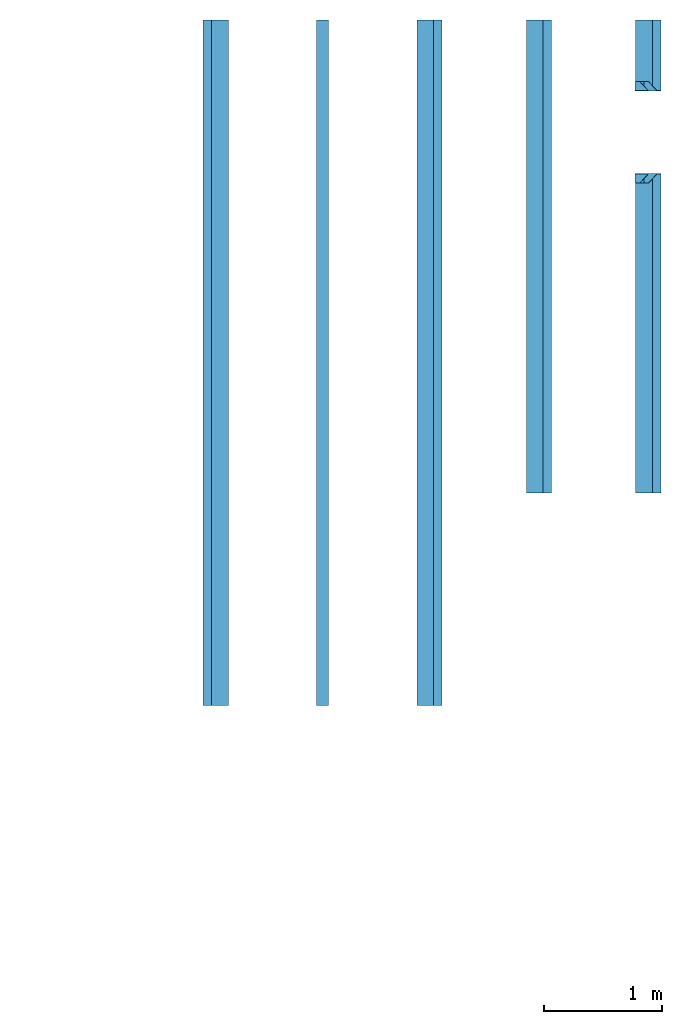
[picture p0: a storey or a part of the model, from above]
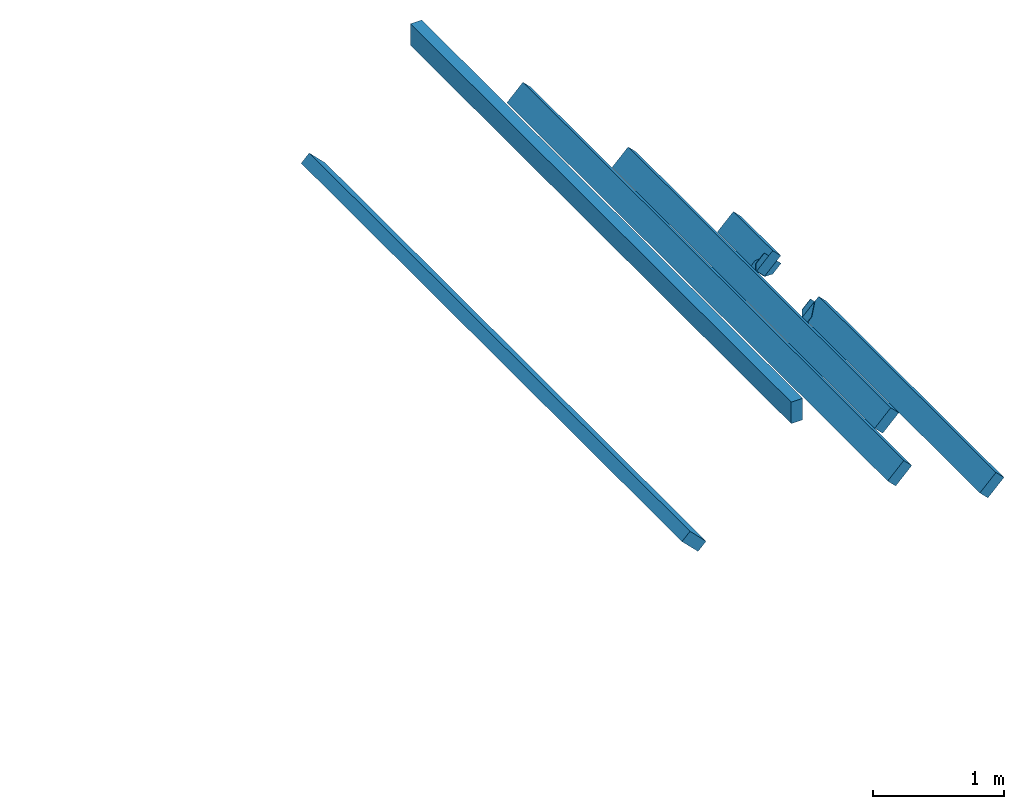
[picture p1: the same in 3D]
Properties of the parts of a building model (IFC4)

# File
Description: ViewDefinition [ReferenceView_V1.2]
File name: Building-Structural.ifc
Time: 2024-11-14T11:09:12
Written by: IFC-manager for SketchUp (5.3.3)
Made in: SketchUp 2024 (24.0.594)

# IfcProject, ifc silly sample scene - project
Description: Demystifying IFC with a playful scene using diverse building elements and compositions.

# IfcSite (2)
RefElevation: 0 mm
Name | Description
environment - site | A sample scene environment, showcasing the surrounding landscape.
house - site | Smoke curls from a friendly chimney, promising warmth within this idyllic hilltop house.

# IfcBuilding, Single-family house
Description: The main building structure, providing shelter and space.; LongName: house - building; Classification: E-AAA Single-family house (CCI Construction)
Pset_BuildingCommon - ConstructionMethod: new construction

# IfcBuildingStorey, 00 groundfloor
In: Single-family house
Description: The ground floor, forming the base level of the building.; Elevation: -1.80478e-12 mm

# IfcBeam: house - girder (6)
In: Single-family house
Type - Description: A strong girder, providing essential support for structures.; ElementType: girder_segment; PredefinedType: USERDEFINED
Material: wood_spruce_beam
Pset_BeamCommon - IsExternal: no; LoadBearing: yes
Qto_BeamBaseQuantities - CrossSectionArea: 0.02 m2
Name | NetVolume (m3) | Length (mm)
girder | 0.054 | 2700
3 x girder | 0.116 | 5800
girder | 0.012 | 600
girder | 0.08 | 4000

# IfcBuildingElementProxy, Group#21
In: 00 groundfloor
Material: Default

# IfcBuildingElementProxy: geo-reference
In: environment - site
Type - Description: The reference point for transforming the local engineering coordinate system into the coordinate reference system of the underlying map.; ElementType: origin; PredefinedType: USERDEFINED
Material: virtual_black

# IfcBuildingElementProxy: origin
In: house - site
Type - Description: The local position for coordination of aspect models.; ElementType: origin; PredefinedType: USERDEFINED
Material: virtual_white

# IfcChimney: house - chimney
In: 00 groundfloor
Type - Description: A chimney, standing tall and proud, guiding smoke away from the home.; ElementType: flue; PredefinedType: USERDEFINED
Material: stone_sand-lime

# IfcDiscreteAccessory: beam shoe (2)
In: Single-family house
Type - Description: A robust shoe, providing stable support for beams.; ElementType: shoe; PredefinedType: SHOE
Material: metal_steel-galvanized

# IfcFooting: house - foundation
In: 00 groundfloor
Type - Description: A house strip footing, ensuring stability and support.; ElementType: strip_footing; PredefinedType: STRIP_FOOTING
Material: concrete_reinforced_in-situ

# IfcRoof: house - roof
In: Single-family house
Type - Description: A sturdy roof, sheltering the house from the elements.; ElementType: gable_roof; PredefinedType: GABLE_ROOF
Pset_RoofCommon - IsExternal: yes

# IfcWall: house - inner wall
In: 00 groundfloor
Type - Description: A solid inner wall, providing structural support within the house.; ElementType: solidwall; PredefinedType: SOLIDWALL
Material: stone_sand-lime
Pset_WallCommon - IsExternal: no; LoadBearing: yes
Qto_WallBaseQuantities - NetVolume: 3.04457 m3; Width: 200 mm; Length: 3900 mm; NetSideArea: 15.2229 m2

# IfcWall: house - outer wall - house back
In: 00 groundfloor
Type - Description: A solid outer wall, forming the back of the house.; ElementType: solidwall; PredefinedType: SOLIDWALL
Material: stone_sand-lime
Pset_WallCommon - IsExternal: yes; LoadBearing: yes
Qto_WallBaseQuantities - NetVolume: 4.28652 m3; Width: 200 mm; Length: 5200 mm; NetSideArea: 21.4326 m2

# IfcWall: house - outer wall - house front
In: 00 groundfloor
Type - Description: A solid outer wall, forming the front of the house.; ElementType: solidwall; PredefinedType: SOLIDWALL
Material: stone_sand-lime
Pset_WallCommon - IsExternal: yes; LoadBearing: yes
Qto_WallBaseQuantities - NetVolume: 2.93131 m3; Width: 200 mm; Length: 3800 mm; NetSideArea: 14.6565 m2

# IfcWall: house - outer wall - house front right
In: 00 groundfloor
Type - Description: A solid outer wall, forming the front right side of the house.; ElementType: solidwall; PredefinedType: SOLIDWALL
Material: stone_sand-lime
Pset_WallCommon - IsExternal: yes
Qto_WallBaseQuantities - NetVolume: 0.745691 m3; Width: 200 mm; Length: 1300 mm; NetSideArea: 3.72846 m2
